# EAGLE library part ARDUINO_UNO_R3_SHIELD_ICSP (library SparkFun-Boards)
Arduino R3 Shield Footprint with ICSP Header Includes pins for 6-pin (2x3) ICSP Header. Compatible with Leonardo boards that require SPI pin connections via this header. SparkFun Products: CryptoShield microSD Shield R3 Stackable Headers Kit

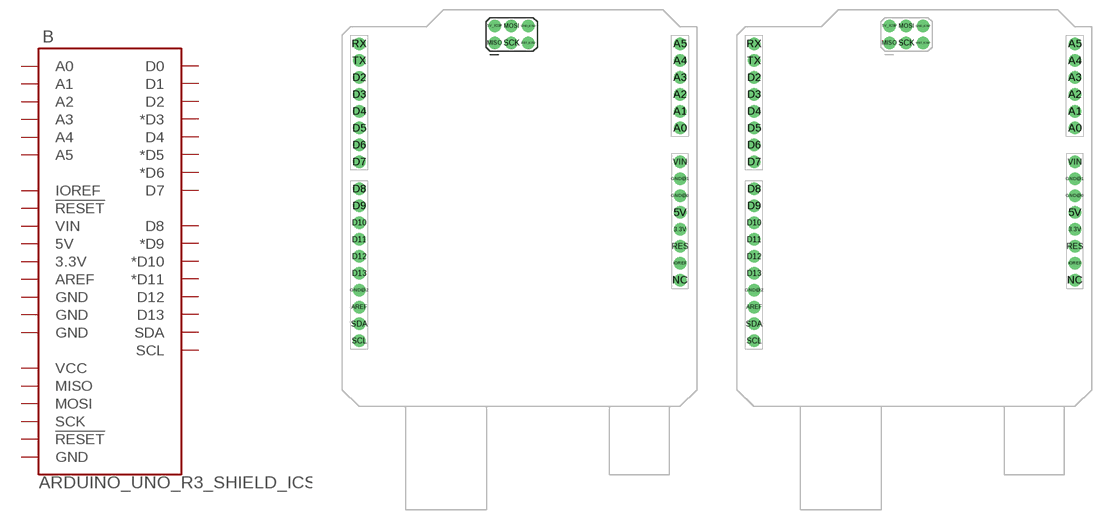
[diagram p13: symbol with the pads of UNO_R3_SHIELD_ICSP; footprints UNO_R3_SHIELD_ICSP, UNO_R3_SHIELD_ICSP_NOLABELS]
Designator prefix B

## ARDUINO_UNO_R3_SHIELD_ICSP  [UNO_R3_SHIELD_ICSP]
3.3V  3.3V
5V  5V
5V_ICSP  VCC
A0  A0
A1  A1
A2  A2
A3  A3
A4  A4
A5  A5
AREF  AREF
D2  D2
D3  *D3
D4  D4
D5  *D5
D6  *D6
D7  D7
D8  D8
D9  *D9
D10  *D10
D11  *D11
D12  D12
D13  D13
GND@0  GND
GND@1  GND
GND@2  GND
GND_ICSP  GND
IOREF  IOREF
MISO  MISO
MOSI  MOSI
RES  !RESET!
RST_ICSP  !RESET!
RX  D0
SCK  SCK
SCL  SCL
SDA  SDA
TX  D1
VIN  VIN

## ARDUINO_UNO_R3_SHIELD_ICSP-NO_LABELS  [UNO_R3_SHIELD_ICSP_NOLABELS]
Pads as for UNO_R3_SHIELD_ICSP

## Footprint UNO_R3_SHIELD_ICSP (pad centres in mm)
Arduino Uno-Compatible Footprint with ICSP No mounting holes. Specifications: Pin count: 38 Pin pitch: 0.1" Area:2.1x2.35" Example device(s): Arduino Uno R3 Shield ICSP
drill 1.016 pad 1.88: 3.3V 24.13,-3.81; 5V 24.13,-1.27; 5V_ICSP -3.76,26.81; A0 24.13,11.43; A1 24.13,13.97; A2 24.13,16.51; A3 24.13,19.05; A4 24.13,21.59; A5 24.13,24.13; AREF -24.13,-15.494; D2 -24.13,19.05; D3 -24.13,16.51; D4 -24.13,13.97; D5 -24.13,11.43; D6 -24.13,8.89; D7 -24.13,6.35; D8 -24.13,2.286; D9 -24.13,-0.254; D10 -24.13,-2.794; D11 -24.13,-5.334; D12 -24.13,-7.874; D13 -24.13,-10.414; GND@0 24.13,1.27; GND@1 24.13,3.81; GND@2 -24.13,-12.954; GND_ICSP 1.32,26.81; IOREF 24.13,-8.89; MISO -3.76,24.27; MOSI -1.22,26.81; NC 24.13,-11.43; RES 24.13,-6.35; RST_ICSP 1.32,24.27; RX -24.13,24.13; SCK -1.22,24.27; SCL -24.13,-20.574; SDA -24.13,-18.034; TX -24.13,21.59; VIN 24.13,6.35

## Footprint UNO_R3_SHIELD_ICSP_NOLABELS (pad centres in mm)
Arduino Uno-Compatible Footprint with ICSP No mounting holes, no silk labels on pins. Specifications: Pin count: 38 Pin pitch: 0.1" Area:2.1x2.35" Example device(s): Arduino Uno R3 Shield ICSP
drill 1.016 pad 1.88: 3.3V 24.13,-3.81; 5V 24.13,-1.27; 5V_ICSP -3.76,26.81; A0 24.13,11.43; A1 24.13,13.97; A2 24.13,16.51; A3 24.13,19.05; A4 24.13,21.59; A5 24.13,24.13; AREF -24.13,-15.494; D2 -24.13,19.05; D3 -24.13,16.51; D4 -24.13,13.97; D5 -24.13,11.43; D6 -24.13,8.89; D7 -24.13,6.35; D8 -24.13,2.286; D9 -24.13,-0.254; D10 -24.13,-2.794; D11 -24.13,-5.334; D12 -24.13,-7.874; D13 -24.13,-10.414; GND@0 24.13,1.27; GND@1 24.13,3.81; GND@2 -24.13,-12.954; GND_ICSP 1.32,26.81; IOREF 24.13,-8.89; MISO -3.76,24.27; MOSI -1.22,26.81; NC 24.13,-11.43; RES 24.13,-6.35; RST_ICSP 1.32,24.27; RX -24.13,24.13; SCK -1.22,24.27; SCL -24.13,-20.574; SDA -24.13,-18.034; TX -24.13,21.59; VIN 24.13,6.35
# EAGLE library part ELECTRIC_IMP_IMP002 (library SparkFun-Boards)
Electric Imp Module imp002 Datasheet SparkFun Products SparkFun Electric Imp imp002 Breakout (BOB-12958)

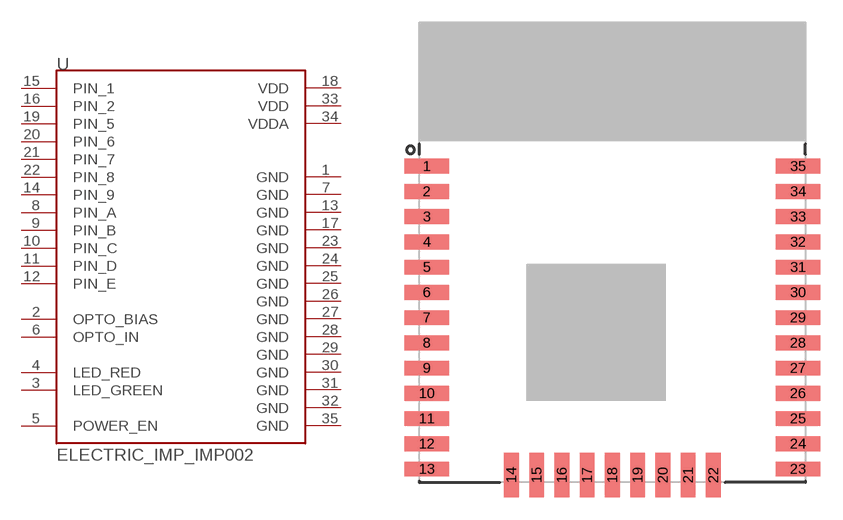
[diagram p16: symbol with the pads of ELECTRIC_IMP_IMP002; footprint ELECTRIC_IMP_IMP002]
Designator prefix U

## ELECTRIC_IMP_IMP002 (PROD_ID: IC-12130; VALUE: imp002)  [ELECTRIC_IMP_IMP002]
1  GND
2  OPTO_BIAS
3  LED_GREEN
4  LED_RED
5  POWER_EN
6  OPTO_IN
7  GND
8  PIN_A
9  PIN_B
10  PIN_C
11  PIN_D
12  PIN_E
13  GND
14  PIN_9
15  PIN_1
16  PIN_2
17  GND
18  VDD
19  PIN_5
20  PIN_6
21  PIN_7
22  PIN_8
23  GND
24  GND
25  GND
26  GND
27  GND
28  GND
29  GND
30  GND
31  GND
32  GND
33  VDD
34  VDDA
35  GND

## Footprint ELECTRIC_IMP_IMP002 (pad centres in mm)
smd 3 x 1: 1 -12.5,5.8; 2 -12.5,4.1; 3 -12.5,2.4; 4 -12.5,0.7; 5 -12.5,-1; 6 -12.5,-2.7; 7 -12.5,-4.4; 8 -12.5,-6.1; 9 -12.5,-7.8; 10 -12.5,-9.5; 11 -12.5,-11.2; 12 -12.5,-12.9; 13 -12.5,-14.6; 23 12.5,-14.6; 24 12.5,-12.9; 25 12.5,-11.2; 26 12.5,-9.5; 27 12.5,-7.8; 28 12.5,-6.1; 29 12.5,-4.4; 30 12.5,-2.7; 31 12.5,-1; 32 12.5,0.7; 33 12.5,2.4; 34 12.5,4.1; 35 12.5,5.8
smd 1 x 3: 14 -6.8,-15; 15 -5.1,-15; 16 -3.4,-15; 17 -1.7,-15; 18 0,-15; 19 1.7,-15; 20 3.4,-15; 21 5.1,-15; 22 6.8,-15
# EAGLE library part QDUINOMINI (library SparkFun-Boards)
Qduino Mini Board Outline and Pins Board outline for SparkFun Qduino Mini

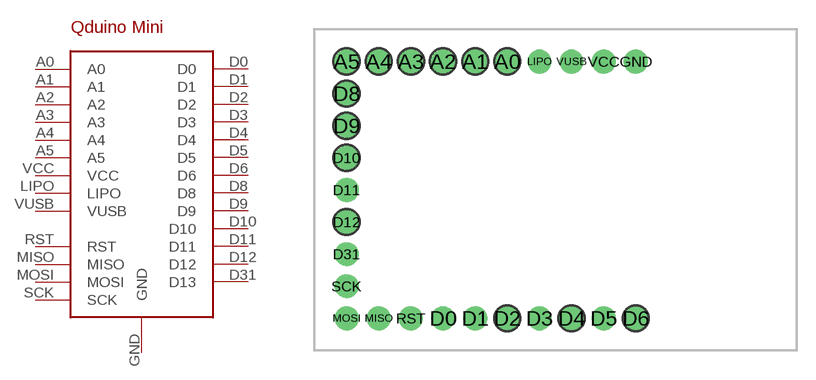
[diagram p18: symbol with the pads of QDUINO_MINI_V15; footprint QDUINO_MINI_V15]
Designator prefix BOARD

## QDUINOMINI  [QDUINO_MINI_V15]
A0  A0
A1  A1
A2  A2
A3  A3
A4  A4
A5  A5
D0  D0
D1  D1
D2  D2
D3  D3
D4  D4
D5  D5
D6  D6
D8  D8
D9  D9
D10  D10
D11  D11
D12  D12
D31  D13
GND  GND
LIPO  LIPO
MISO  MISO
MOSI  MOSI
RST  RST
SCK  SCK
VCC  VCC
VUSB  VUSB

## Footprint QDUINO_MINI_V15 (pad centres in mm)
Qduino Mini Board Outline and Pins Board outline for SparkFun Qduino Mini Devices using: QDUINOMINI
drill 1.016 pad 1.88: A0 -3.81,10.16; A1 -6.35,10.16; A2 -8.89,10.16; A3 -11.43,10.16; A4 -13.97,10.16; A5 -16.51,10.16; D0 -8.89,-10.16; D1 -6.35,-10.16; D2 -3.81,-10.16; D3 -1.27,-10.16; D4 1.27,-10.16; D5 3.81,-10.16; D6 6.35,-10.16; D8 -16.51,7.62; D9 -16.51,5.08; D10 -16.51,2.54; D11 -16.51,0; D12 -16.51,-2.54; D31 -16.51,-5.08; GND 6.35,10.16; LIPO -1.27,10.16; MISO -13.97,-10.16; MOSI -16.51,-10.16; RST -11.43,-10.16; SCK -16.51,-7.62; VCC 3.81,10.16; VUSB 1.27,10.16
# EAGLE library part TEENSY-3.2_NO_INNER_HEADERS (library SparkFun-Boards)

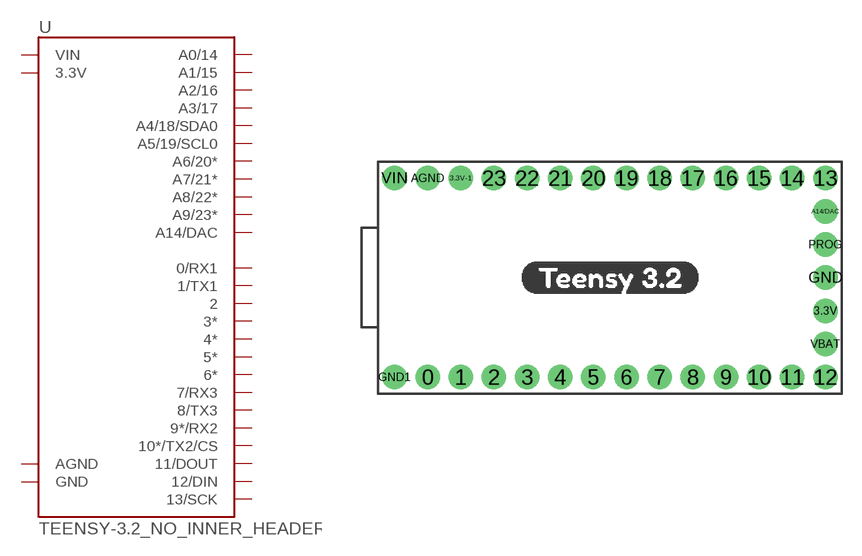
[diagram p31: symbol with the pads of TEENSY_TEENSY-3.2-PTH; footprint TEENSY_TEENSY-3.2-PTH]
Designator prefix U

## TEENSY-3.2_NO_INNER_HEADERSPTH  [TEENSY_TEENSY-3.2-PTH]
0  0/RX1
1  1/TX1
2  2
3  3*
3.3V  3.3V
3.3V-1  3.3V
4  4*
5  5*
6  6*
7  7/RX3
8  8/TX3
9  9*/RX2
10  10*/TX2/CS
11  11/DOUT
12  12/DIN
13  13/SCK
14  A0/14
15  A1/15
16  A2/16
17  A3/17
18  A4/18/SDA0
19  A5/19/SCL0
20  A6/20*
21  A7/21*
22  A8/22*
23  A9/23*
A14/DAC  A14/DAC
AGND  AGND
GND  GND
GND1  GND
VIN  VIN

## Footprint TEENSY_TEENSY-3.2-PTH (pad centres in mm)
drill 1.016 pad 1.88: 0 -13.97,-7.62; 1 -11.43,-7.62; 2 -8.89,-7.62; 3 -6.35,-7.62; 3.3V 16.51,-2.54; 3.3V-1 -11.43,7.62; 4 -3.81,-7.62; 5 -1.27,-7.62; 6 1.27,-7.62; 7 3.81,-7.62; 8 6.35,-7.62; 9 8.89,-7.62; 10 11.43,-7.62; 11 13.97,-7.62; 12 16.51,-7.62; 13 16.51,7.62; 14 13.97,7.62; 15 11.43,7.62; 16 8.89,7.62; 17 6.35,7.62; 18 3.81,7.62; 19 1.27,7.62; 20 -1.27,7.62; 21 -3.81,7.62; 22 -6.35,7.62; 23 -8.89,7.62; A14/DAC 16.51,5.08; AGND -13.97,7.62; GND 16.51,0; GND1 -16.51,-7.62; PROG 16.51,2.54; VBAT 16.51,-5.08; VIN -16.51,7.62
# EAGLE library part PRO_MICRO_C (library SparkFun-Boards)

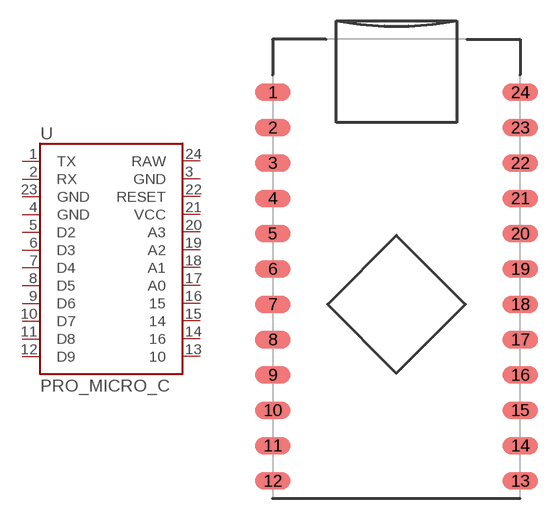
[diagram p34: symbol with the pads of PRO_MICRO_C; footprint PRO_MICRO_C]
Designator prefix U

## PRO_MICRO_C  [PRO_MICRO_C]
1  TX
2  RX
3  GND
4  GND
5  D2
6  D3
7  D4
8  D5
9  D6
10  D7
11  D8
12  D9
13  10
14  16
15  14
16  15
17  A0
18  A1
19  A2
20  A3
21  VCC
22  RESET
23  GND
24  RAW

## Footprint PRO_MICRO_C (pad centres in mm)
smd 2.54 x 1.27: 1 -8.89,12.7; 2 -8.89,10.16; 3 -8.89,7.62; 4 -8.89,5.08; 5 -8.89,2.54; 6 -8.89,0; 7 -8.89,-2.54; 8 -8.89,-5.08; 9 -8.89,-7.62; 10 -8.89,-10.16; 11 -8.89,-12.7; 12 -8.89,-15.24; 13 8.89,-15.24; 14 8.89,-12.7; 15 8.89,-10.16; 16 8.89,-7.62; 17 8.89,-5.08; 18 8.89,-2.54; 19 8.89,0; 20 8.89,2.54; 21 8.89,5.08; 22 8.89,7.62; 23 8.89,10.16; 24 8.89,12.7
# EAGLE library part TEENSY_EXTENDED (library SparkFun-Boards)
Teensy Footprint Extended Mechanical footprint with connectors for Teensy Development Board with ARM Cortex. SparkFun Products: Teensy 4.1 Teensy 3.6 Teensy 3.5 SparkFun Qwiic Shield for Teensy Extended Teensy Stackable Header Kit (Longer Version)

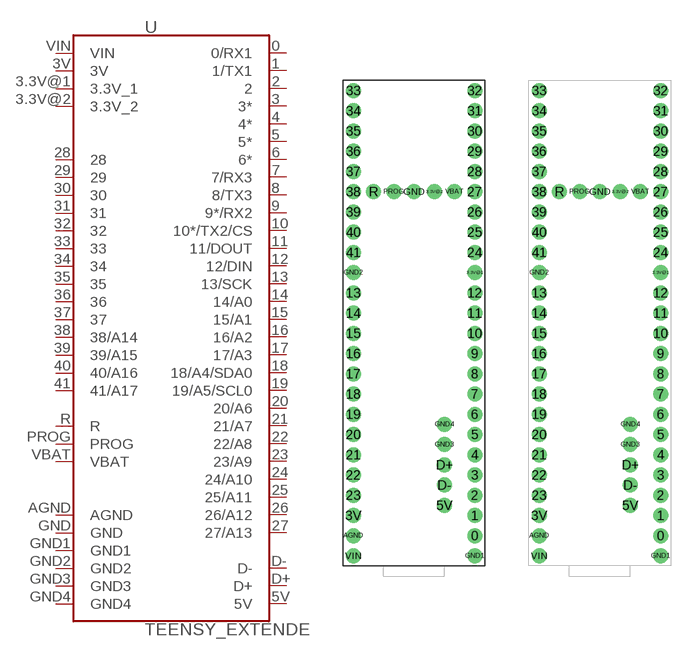
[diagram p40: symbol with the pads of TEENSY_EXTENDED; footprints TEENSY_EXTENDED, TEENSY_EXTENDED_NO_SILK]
Designator prefix -

## TEENSY_EXTENDEDW_SILK  [TEENSY_EXTENDED]
0  0/RX1
1  1/TX1
2  2
3  3*
3.3V@1  3.3V_1  pwr
3.3V@2  3.3V_2  pwr
3V  3V  pwr
4  4*
5  5*
5V  5V  pwr
6  6*
7  7/RX3
8  8/TX3
9  9*/RX2
10  10*/TX2/CS
11  11/DOUT
12  12/DIN
13  13/SCK
14  14/A0
15  15/A1
16  16/A2
17  17/A3
18  18/A4/SDA0
19  19/A5/SCL0
20  20/A6
21  21/A7
22  22/A8
23  23/A9
24  24/A10
25  25/A11
26  26/A12
27  27/A13
28  28
29  29
30  30
31  31
32  32
33  33
34  34
35  35
36  36
37  37
38  38/A14
39  39/A15
40  40/A16
41  41/A17
AGND  AGND  pwr
D+  D+  pwr
D-  D-  pwr
GND  GND  pwr
GND1  GND1  pwr
GND2  GND2  pwr
GND3  GND3  pwr
GND4  GND4
PROG  PROG
R  R
VBAT  VBAT  pwr
VIN  VIN  pwr

## TEENSY_EXTENDEDNO_SILK  [TEENSY_EXTENDED_NO_SILK]
Pads as for TEENSY_EXTENDED

## Footprint TEENSY_EXTENDED (pad centres in mm)
Teensy 3 Footprint Specifications: Pin count:37 Pin pitch: 0.1" Area:0.7x1.4" Example device(s): Teensy 3.1
drill 1.016 pad 1.88: 0 7.62,-13.97; 1 7.62,-11.43; 2 7.62,-8.89; 3 7.62,-6.35; 3.3V@1 7.62,19.05; 3.3V@2 2.54,29.21; 3V -7.62,-11.43; 4 7.62,-3.81; 5 7.62,-1.27; 5V 3.81,-10.16; 6 7.62,1.27; 7 7.62,3.81; 8 7.62,6.35; 9 7.62,8.89; 10 7.62,11.43; 11 7.62,13.97; 12 7.62,16.51; 13 -7.62,16.51; 14 -7.62,13.97; 15 -7.62,11.43; 16 -7.62,8.89; 17 -7.62,6.35; 18 -7.62,3.81; 19 -7.62,1.27; 20 -7.62,-1.27; 21 -7.62,-3.81; 22 -7.62,-6.35; 23 -7.62,-8.89; 24 7.62,21.59; 25 7.62,24.13; 26 7.62,26.67; 27 7.62,29.21; 28 7.62,31.75; 29 7.62,34.29; 30 7.62,36.83; 31 7.62,39.37; 32 7.62,41.91; 33 -7.62,41.91; 34 -7.62,39.37; 35 -7.62,36.83; 36 -7.62,34.29; 37 -7.62,31.75; 38 -7.62,29.21; 39 -7.62,26.67; 40 -7.62,24.13; 41 -7.62,21.59; AGND -7.62,-13.97; D+ 3.81,-5.08; D- 3.81,-7.62; GND 0,29.21; GND1 7.62,-16.51; GND2 -7.62,19.05; GND3 3.81,-2.54; GND4 3.81,0; PROG -2.54,29.21; R -5.08,29.21; VBAT 5.08,29.21; VIN -7.62,-16.51

## Footprint TEENSY_EXTENDED_NO_SILK (pad centres in mm)
Teensy 3 Footprint Specifications: Pin count:37 Pin pitch: 0.1" Area:0.7x1.4" Example device(s): Teensy 3.1
drill 1.016 pad 1.88: 0 7.62,-13.97; 1 7.62,-11.43; 2 7.62,-8.89; 3 7.62,-6.35; 3.3V@1 7.62,19.05; 3.3V@2 2.54,29.21; 3V -7.62,-11.43; 4 7.62,-3.81; 5 7.62,-1.27; 5V 3.81,-10.16; 6 7.62,1.27; 7 7.62,3.81; 8 7.62,6.35; 9 7.62,8.89; 10 7.62,11.43; 11 7.62,13.97; 12 7.62,16.51; 13 -7.62,16.51; 14 -7.62,13.97; 15 -7.62,11.43; 16 -7.62,8.89; 17 -7.62,6.35; 18 -7.62,3.81; 19 -7.62,1.27; 20 -7.62,-1.27; 21 -7.62,-3.81; 22 -7.62,-6.35; 23 -7.62,-8.89; 24 7.62,21.59; 25 7.62,24.13; 26 7.62,26.67; 27 7.62,29.21; 28 7.62,31.75; 29 7.62,34.29; 30 7.62,36.83; 31 7.62,39.37; 32 7.62,41.91; 33 -7.62,41.91; 34 -7.62,39.37; 35 -7.62,36.83; 36 -7.62,34.29; 37 -7.62,31.75; 38 -7.62,29.21; 39 -7.62,26.67; 40 -7.62,24.13; 41 -7.62,21.59; AGND -7.62,-13.97; D+ 3.81,-5.08; D- 3.81,-7.62; GND 0,29.21; GND1 7.62,-16.51; GND2 -7.62,19.05; GND3 3.81,-2.54; GND4 3.81,0; PROG -2.54,29.21; R -5.08,29.21; VBAT 5.08,29.21; VIN -7.62,-16.51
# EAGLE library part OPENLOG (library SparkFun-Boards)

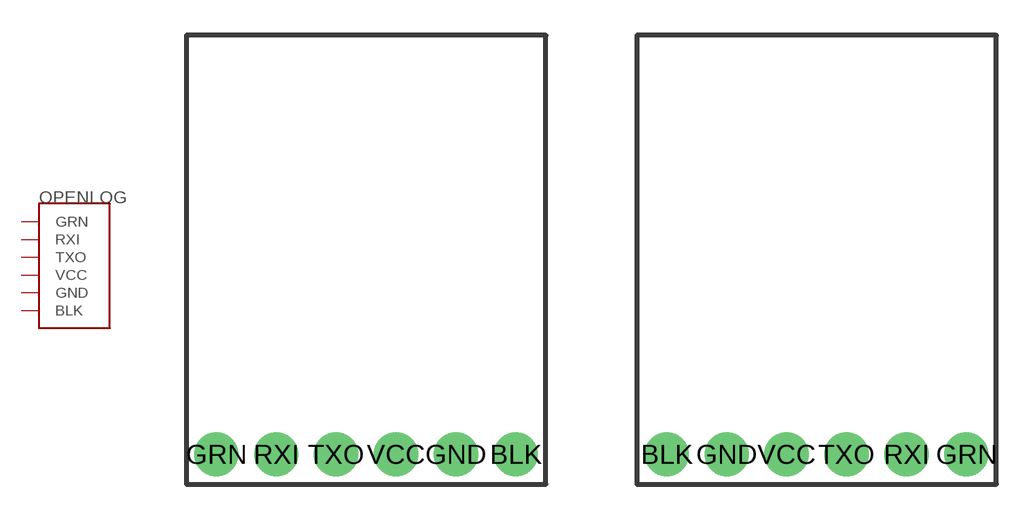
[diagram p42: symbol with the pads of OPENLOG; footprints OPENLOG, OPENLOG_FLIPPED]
Designator prefix -

## OPENLOG  [OPENLOG]
BLK  BLK
GND  GND  pwr
GRN  GRN
RXI  RXI  in
TXO  TXO  out
VCC  VCC  pwr

## OPENLOG_FLIPPED  [OPENLOG_FLIPPED]
Pads as for OPENLOG

## Footprint OPENLOG (pad centres in mm)
drill 1.016 pad 1.88: BLK 13.97,1.27; GND 11.43,1.27; GRN 1.27,1.27; RXI 3.81,1.27; TXO 6.35,1.27; VCC 8.89,1.27

## Footprint OPENLOG_FLIPPED (pad centres in mm)
drill 1.016 pad 1.88: BLK 1.27,1.27; GND 3.81,1.27; GRN 13.97,1.27; RXI 11.43,1.27; TXO 8.89,1.27; VCC 6.35,1.27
